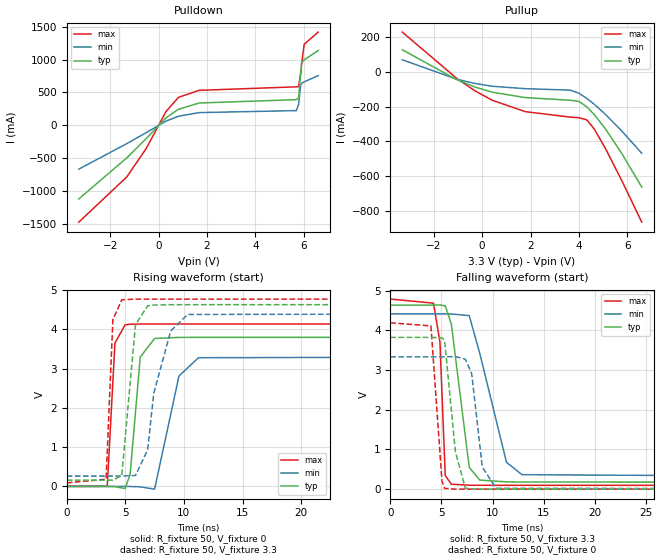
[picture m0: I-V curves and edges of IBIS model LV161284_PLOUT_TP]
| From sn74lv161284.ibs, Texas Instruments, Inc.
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[Model]   LV161284_PLOUT_TP
Model_type  Output
Vref =   0
Rref =   500
Cref =   50p
Vmeas =   1.4
| variable   typ   min   max
C_comp   9.71pF   6.01pF   13.91pF
| C_pullup   9.45pF   6.72pF   10.69pF
| C_pulldown   9.97pF   6.01pF   13.91pF
[Temperature Range]   40   100   -40
| Ambient temperature   25   85   -40
[Voltage range]   3.3   3   3.6
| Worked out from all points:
|   slope of the pulldown table from 0 to 0.495 V, typ, clamps not added: 2.94 ohm
|   slope of the pullup table from 0 to 0.495 V, typ, clamps not added: 26.2 ohm
|   rising waveform, R_fixture 50, V_fixture 0: 20-80 % time 587ps typ, 1.01ns min, 342ps max; typ from 0 V to 3.8 V
|   falling waveform, R_fixture 50, V_fixture 3.3: 20-80 % time 1.25ns typ, 2.38ns min, 422ps max; typ from 4.63 V to 0.171 V
|   rising waveform, R_fixture 50, V_fixture 3.3: 20-80 % time 694ps typ, 1.64ns min, 324ps max; typ from 0.161 V to 4.63 V
|   falling waveform, R_fixture 50, V_fixture 0: 20-80 % time 756ps typ, 826ps min, 627ps max; typ from 3.82 V to 0 V
[Pulldown]
| LV161284_PLOUT_TP
|   Voltage   I(typ)   I(min)   I(max)
-3.3V     -1.125A    -670.7mA   -1.479A
-1.315V   -498mA     -281.2mA   -789.1mA
-505mV    -202mA     -111.8mA   -352.1mA
305mV     111.9mA    62.04mA    207.4mA
820mV     243mA      136.8mA    424.4mA
1.675V    338.6mA    192.1mA    531.7mA
5.695V    389.6mA    222.6mA    585.2mA
5.79V     419.2mA    316.1mA    590.9mA
5.87V     779.2mA    606.5mA    773.1mA
5.915V    957.9mA    639.7mA    931mA
6.02V     996.7mA    661.1mA    1.234A
6.6V      1.139A     756.9mA    1.42A
[Pullup]
| LV161284_PLOUT_TP
|   Voltage   I(typ)   I(min)   I(max)
-3.3V     126mA      68.51mA    227.5mA
-1.06V    -45.03mA   -42.6mA    -37.28mA
-320mV    -86.79mA   -66.91mA   -108mA
420mV     -117.8mA   -83.56mA   -164.1mA
1.785V    -148.7mA   -97.45mA   -229.3mA
3.64V     -163.9mA   -105.8mA   -260.8mA
4.005V    -170.9mA   -123.9mA   -264.2mA
4.33V     -202.1mA   -153.5mA   -276.7mA
4.63V     -245.2mA   -186.3mA   -328.4mA
5.09V     -326.7mA   -244mA     -438.8mA
5.77V     -468.9mA   -340mA     -624.2mA
6.6V      -662.8mA   -468.2mA   -864.1mA
[Ramp]
| LV161284_PLOUT_TP
| variable   typ   min   max
dV/dt_r   2.32/5.98E-10   2.03/1.03E-09   2.49/3.52E-10
dV/dt_f   2.68/1.25E-09   2.48/2.38E-09   2.82/4.29E-10
R_load = 50
[Rising Waveform]
| LV161284_PLOUT_TP
R_fixture =   50
C_fixture =   0
L_fixture =   0
V_fixture =   0
V_fixture_min = 0
V_fixture_max = 0
|   Time   V(typ)   V(min)   V(max)
0s        17.54nV    82.91nV    413.1nV
3.455ns   118.9uV    -574.9nV   3.687mV
4.11ns    -5.713mV   -4.708uV   3.649V
4.975ns   -52.26mV   126.6uV    4.116V
5.405ns   303.8mV    -1.201mV   4.13V
6.27ns    3.295V     -10.72mV   4.136V
7.495ns   3.768V     -69.61mV   4.137V
9.575ns   3.796V     2.813V     4.137V
11.24ns   3.797V     3.278V     4.137V
70ns      3.797V     3.319V     4.137V
[Falling Waveform]
| LV161284_PLOUT_TP
R_fixture =   50
C_fixture =   0
L_fixture =   0
V_fixture =   3.3
V_fixture_min = 3
V_fixture_max = 3.6
|   Time   V(typ)   V(min)   V(max)
0s        4.635V     4.412V     4.787V
4.22ns    4.635V     4.412V     4.684V
4.85ns    4.638V     4.412V     3.707V
5.37ns    4.617V     4.412V     344.1mV
5.965ns   4.157V     4.411V     125.1mV
7.715ns   548.4mV    4.37V      99.04mV
8.75ns    228.4mV    3.416V     97.85mV
11.36ns   183.9mV    675.5mV    96.64mV
12.88ns   180.3mV    364mV      96.28mV
70ns      171.1mV    287.6mV    94.22mV
[Rising Waveform]
| LV161284_PLOUT_TP
R_fixture =   50
C_fixture =   0
L_fixture =   0
V_fixture =   3.3
V_fixture_min = 3
V_fixture_max = 3.6
|   Time   V(typ)   V(min)   V(max)
0s        161.3mV    265mV      91.9mV
3.355ns   161.3mV    265mV      183mV
3.935ns   160.9mV    265mV      4.248V
4.69ns    275.2mV    264.8mV    4.752V
5.865ns   4.121V     280.1mV    4.771V
6.9ns     4.6V       933.2mV    4.772V
7.425ns   4.62V      2.373V     4.772V
8.87ns    4.628V     3.96V      4.772V
10.31ns   4.629V     4.379V     4.772V
70ns      4.629V     4.415V     4.772V
[Falling Waveform]
| LV161284_PLOUT_TP
R_fixture =   50
C_fixture =   0
L_fixture =   0
V_fixture =   0
V_fixture_min = 0
V_fixture_max = 0
|   Time   V(typ)   V(min)   V(max)
0s        3.822V     3.331V     4.19V
3.97ns    3.822V     3.331V     4.111V
5.05ns    3.812V     3.331V     198.3mV
5.305ns   3.742V     3.331V     19.7mV
6.365ns   936.8mV    3.339V     2.096mV
7.335ns   24.9mV     3.273V     490.1uV
7.955ns   7.519mV    2.911V     309.7uV
8.99ns    1.947mV    558mV      190.7uV
10.33ns   559uV      23.45mV    125.3uV
70ns      6.295uV    10.89uV    7.719uV
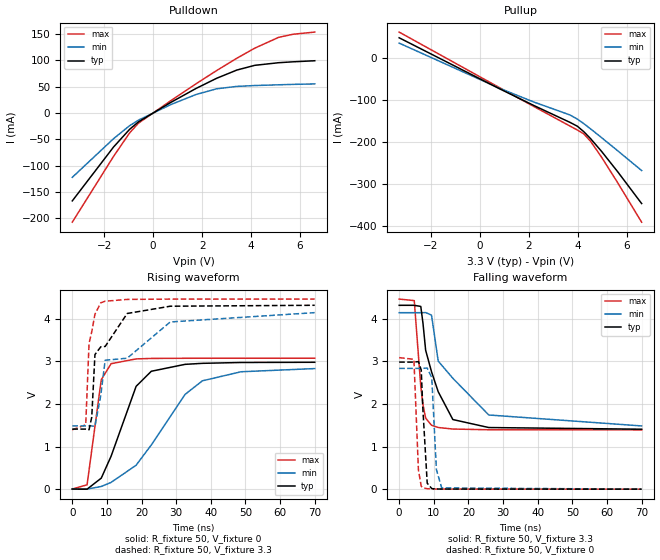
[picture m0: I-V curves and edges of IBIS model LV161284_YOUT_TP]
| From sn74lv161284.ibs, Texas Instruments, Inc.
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[Model]   LV161284_YOUT_TP
Model_type  Output
Vref =   3.3
Rref =   500
Cref =   50p
Vmeas =   1.4
| variable   typ   min   max
C_comp   3.71pF   2.21pF   4.90pF
| C_pullup   3.07pF   2.21pF   4.10pF
| C_pulldown   4.34pF   3.78pF   4.90pF
[Temperature Range]   40   100   -40
| Ambient temperature   25   85   -40
[Voltage range]   3.3   3   3.6
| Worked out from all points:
|   slope of the pulldown table from 0 to 0.495 V, typ, clamps not added: 36.1 ohm
|   slope of the pullup table from 0 to 0.495 V, typ, clamps not added: 34.3 ohm
|   rising waveform, R_fixture 50, V_fixture 0: 20-80 % time 7.91ns typ, 14.5ns min, 3ns max; typ from 0 V to 2.98 V
|   falling waveform, R_fixture 50, V_fixture 3.3: 20-80 % time 5.61ns typ, 11.6ns min, 1.86ns max; typ from 4.32 V to 1.41 V
|   rising waveform, R_fixture 50, V_fixture 3.3: 20-80 % time 6.84ns typ, 15.1ns min, 1.78ns max; typ from 1.41 V to 4.32 V
|   falling waveform, R_fixture 50, V_fixture 0: 20-80 % time 871ps typ, 949ps min, 733ps max; typ from 2.99 V to 0 V
[Pulldown]
| LV161284_YOUT_TP
|   Voltage   I(typ)   I(min)   I(max)
-3.3V     -167mA     -122.3mA   -207.4mA
-1.615V   -64.77mA   -48.94mA   -82.55mA
-960mV    -31.21mA   -24.31mA   -38.06mA
-595mV    -16.92mA   -13.7mA    -19.41mA
725mV     19.95mA    15.81mA    23.21mA
1.76V     46.53mA    34.97mA    55.41mA
2.595V    65.66mA    45.71mA    80.34mA
3.42V     81.28mA    50.25mA    103.7mA
4.15V     90.22mA    51.87mA    122.8mA
5.13V     95.22mA    53.28mA    143.4mA
5.715V    96.91mA    54.09mA    149.2mA
6.6V      98.93mA    54.94mA    153.3mA
[Pullup]
| LV161284_YOUT_TP
|   Voltage   I(typ)   I(min)   I(max)
-3.3V     47.15mA    34.51mA    60.63mA
760mV     -72.64mA   -71.61mA   -69.87mA
2.21V     -113.7mA   -105.4mA   -116.1mA
3.675V    -153.4mA   -135.8mA   -162.1mA
3.97V     -162.3mA   -145.4mA   -171.3mA
4.235V    -175.2mA   -156.3mA   -180.5mA
4.51V     -191.6mA   -168.5mA   -197.8mA
4.955V    -221.5mA   -189.1mA   -235.1mA
5.625V    -270.6mA   -220.8mA   -296.7mA
6.6V      -345.8mA   -267.6mA   -390mA
[Ramp]
| LV161284_YOUT_TP
| variable   typ   min   max
dV/dt_r   1.80/7.95E-09   1.71/1.46E-08   1.85/3.01E-09
dV/dt_f   1.75/5.61E-09   1.60/1.16E-08   1.85/1.86E-09
R_load = 50
[Rising Waveform]
| LV161284_YOUT_TP
R_fixture =   50
C_fixture =   0
L_fixture =   0
V_fixture =   0
V_fixture_min = 0
V_fixture_max = 0
|   Time   V(typ)   V(min)   V(max)
0s        403nV      1.053uV    7.613uV
4.275ns   -2.244mV   2.427uV    100.5mV
8.37ns    257mV      60.41mV    2.571V
11.21ns   772.7mV    157.1mV    2.946V
18.43ns   2.414V     560.1mV    3.058V
22.82ns   2.768V     1.037V     3.069V
32.55ns   2.93V      2.223V     3.073V
37.55ns   2.954V     2.543V     3.074V
48.71ns   2.974V     2.756V     3.074V
70ns      2.979V     2.831V     3.074V
[Falling Waveform]
| LV161284_YOUT_TP
R_fixture =   50
C_fixture =   0
L_fixture =   0
V_fixture =   3.3
V_fixture_min = 3
V_fixture_max = 3.6
|   Time   V(typ)   V(min)   V(max)
0s        4.32V      4.147V     4.467V
4.36ns    4.32V      4.147V     4.431V
6.245ns   4.294V     4.147V     2.416V
6.885ns   3.895V     4.147V     1.983V
7.645ns   3.266V     4.15V      1.672V
9.34ns    2.761V     4.09V      1.502V
11.28ns   2.289V     3.009V     1.449V
15.5ns    1.636V     2.606V     1.413V
25.87ns   1.448V     1.743V     1.396V
70ns      1.409V     1.486V     1.393V
[Rising Waveform]
| LV161284_YOUT_TP
R_fixture =   50
C_fixture =   0
L_fixture =   0
V_fixture =   3.3
V_fixture_min = 3
V_fixture_max = 3.6
|   Time   V(typ)   V(min)   V(max)
0s        1.409V     1.483V     1.393V
3.885ns   1.409V     1.483V     1.511V
4.84ns    1.393V     1.483V     3.417V
5.62ns    1.69V      1.483V     3.694V
6.545ns   3.16V      1.474V     4.109V
8.24ns    3.343V     2.207V     4.377V
9.495ns   3.35V      3.027V     4.413V
15.85ns   4.125V     3.074V     4.456V
28.28ns   4.296V     3.926V     4.463V
70ns      4.318V     4.145V     4.464V
[Falling Waveform]
| LV161284_YOUT_TP
R_fixture =   50
C_fixture =   0
L_fixture =   0
V_fixture =   0
V_fixture_min = 0
V_fixture_max = 0
|   Time   V(typ)   V(min)   V(max)
0s        2.986V     2.838V     3.091V
4.26ns    2.986V     2.838V     3.051V
5.565ns   2.997V     2.839V     448.9mV
6.375ns   2.801V     2.84V      69.09mV
6.81ns    1.94V      2.84V      35.58mV
8.1ns     140.8mV    2.847V     10.36mV
9.415ns   13.41mV    2.621V     4.764mV
10.75ns   4.422mV    461.5mV    3.198mV
12.28ns   2.353mV    30.04mV    2.299mV
70ns      55.74uV    69.46uV    179.5uV
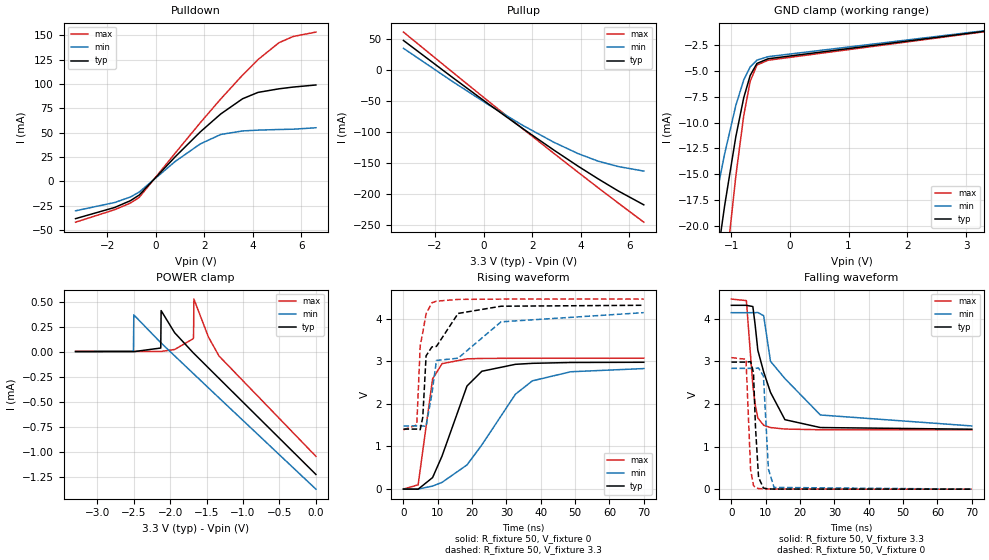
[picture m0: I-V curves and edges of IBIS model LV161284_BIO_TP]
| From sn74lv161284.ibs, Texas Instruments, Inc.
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[Model]   LV161284_BIO_TP
Model_type  I/O
Vinl=0.8
Vinh=2.0
Enable   Active-High
Vref =   3.3
Rref =   500
Cref =   50p
Vmeas =   1.4
| variable   typ   min   max
C_comp   5.52pF   4.67pF   6.22pF
| C_pullup   3.90pF   2.99pF   4.78pF
| C_pulldown   5.17pF   4.57pF   5.68pF
| C_tri-state   5.52pF   4.67pF   6.22pF
[Temperature Range]   40   100   -40
| Ambient temperature   25   85   -40
[Voltage range]   3.3   3   3.6
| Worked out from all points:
|   slope of the pulldown table from 0 to 0.495 V, typ, clamps not added: 37 ohm
|   slope of the pullup table from 0 to 0.495 V, typ, clamps not added: 35.2 ohm
|   rising waveform, R_fixture 50, V_fixture 0: 20-80 % time 7.93ns typ, 14.5ns min, 3.04ns max; typ from 0 V to 2.98 V
|   falling waveform, R_fixture 50, V_fixture 3.3: 20-80 % time 5.65ns typ, 11.6ns min, 1.89ns max; typ from 4.32 V to 1.41 V
|   rising waveform, R_fixture 50, V_fixture 3.3: 20-80 % time 6.87ns typ, 15.1ns min, 1.8ns max; typ from 1.41 V to 4.32 V
|   falling waveform, R_fixture 50, V_fixture 0: 20-80 % time 917ps typ, 992ps min, 764ps max; typ from 2.99 V to 0 V
[GND Clamp]
| LV161284_BIO_TP
|   Voltage   I(typ)   I(min)   I(max)
-3.3V     -132.9mA   -95.54mA   -170.5mA
-1.54V    -36.32mA   -26.12mA   -50.92mA
-1.495V   -34.24mA   -24.64mA   -48.09mA
-1.295V   -25.43mA   -18.32mA   -35.84mA
-1.275V   -24.59mA   -17.72mA   -34.65mA
-1.11V    -18mA      -13.01mA   -25.13mA
-920mV    -11.37mA   -8.353mA   -15.17mA
-785mV    -7.61mA    -5.896mA   -9.329mA
-675mV    -5.466mA   -4.642mA   -6.029mA
-560mV    -4.309mA   -3.992mA   -4.463mA
-370mV    -3.864mA   -3.66mA    -4.005mA
3.3V      -1.226mA   -1.168mA   -1.268mA
[POWER Clamp]
| LV161284_BIO_TP
|   Voltage   I(typ)   I(min)   I(max)
-3.3V     318.9nA    13.56nA    4.426uA
-2.505V   202.9nA    4.995uA    2.684uA
-2.5V     202.5nA    367uA      2.674uA
-2.13V    36.28uA    89.82uA    2.09uA
-2.125V   410uA      86.37uA    2.092uA
-1.94V    189.5uA    -41.39uA   21.68uA
-1.685V   -10.57uA   -217.2uA   128.8uA
-1.68V    -14.2uA    -220.7uA   137.3uA
-1.675V   -17.83uA   -224.1uA   525.1uA
-1.475V   -162.4uA   -361.8uA   145uA
-1.33V    -267.1uA   -461.6uA   -43.55uA
-48.03fV  -1.226mA   -1.373mA   -1.045mA
[Pulldown]
| LV161284_BIO_TP
|   Voltage   I(typ)   I(min)   I(max)
-3.3V     -38.49mA   -30.42mA   -42.13mA
-1.69V    -27.01mA   -21.92mA   -29.3mA
-1.045V   -20.07mA   -16.3mA    -22.51mA
-680mV    -14.27mA   -11.21mA   -16.75mA
810mV     25.23mA    20.41mA    29.02mA
1.84V     50.74mA    38.38mA    60.19mA
2.68V     69.12mA    48.05mA    84.54mA
3.58V     84.76mA    51.67mA    109.1mA
4.215V    91.3mA     52.52mA    125mA
5.08V     94.99mA    53.16mA    142.4mA
5.665V    96.78mA    53.47mA    148.8mA
6.6V      98.93mA    54.94mA    153.3mA
[Pullup]
| LV161284_BIO_TP
|   Voltage   I(typ)   I(min)   I(max)
-3.3V     47.15mA    34.51mA    60.62mA
-1.27V    -12.61mA   -19.15mA   -4.139mA
190mV     -54.74mA   -55.98mA   -50.36mA
1.59V     -93.97mA   -88.92mA   -94.17mA
2.895V    -129.2mA   -116.6mA   -134.5mA
3.9V      -155.3mA   -135mA     -165.1mA
4.715V    -175.4mA   -147mA     -189.7mA
5.54V     -194.8mA   -155.6mA   -214.2mA
6.6V      -217.3mA   -163mA     -245.2mA
[Ramp]
| LV161284_BIO_TP
| variable   typ   min   max
dV/dt_r   1.80/7.97E-09   1.71/1.46E-08   1.85/3.05E-09
dV/dt_f   1.75/5.64E-09   1.60/1.16E-08   1.85/1.89E-09
R_load = 50
[Rising Waveform]
| LV161284_BIO_TP
R_fixture =   50
C_fixture =   0
L_fixture =   0
V_fixture =   0
V_fixture_min = 0
V_fixture_max = 0
|   Time   V(typ)   V(min)   V(max)
0s        419.4nV    1.058uV    7.728uV
4.275ns   -2.507mV   2.249uV    99.21mV
8.485ns   270.1mV    69.85mV    2.588V
11.23ns   774.9mV    156.9mV    2.946V
18.5ns    2.421V     566.3mV    3.059V
22.83ns   2.768V     1.038V     3.069V
32.62ns   2.931V     2.229V     3.073V
37.56ns   2.954V     2.543V     3.074V
48.72ns   2.974V     2.756V     3.074V
70ns      2.979V     2.831V     3.074V
[Falling Waveform]
| LV161284_BIO_TP
R_fixture =   50
C_fixture =   0
L_fixture =   0
V_fixture =   3.3
V_fixture_min = 3
V_fixture_max = 3.6
|   Time   V(typ)   V(min)   V(max)
0s        4.32V      4.147V     4.467V
4.365ns   4.32V      4.147V     4.431V
6.255ns   4.292V     4.147V     2.438V
6.915ns   3.864V     4.147V     1.994V
7.705ns   3.265V     4.151V     1.672V
9.4ns     2.756V     4.076V     1.501V
11.39ns   2.275V     3.006V     1.448V
15.59ns   1.633V     2.599V     1.413V
25.92ns   1.448V     1.743V     1.396V
70ns      1.409V     1.486V     1.393V
[Rising Waveform]
| LV161284_BIO_TP
R_fixture =   50
C_fixture =   0
L_fixture =   0
V_fixture =   3.3
V_fixture_min = 3
V_fixture_max = 3.6
|   Time   V(typ)   V(min)   V(max)
0s        1.409V     1.483V     1.393V
3.885ns   1.409V     1.483V     1.507V
4.875ns   1.395V     1.483V     3.364V
5.625ns   1.686V     1.483V     3.678V
6.59ns    3.131V     1.473V     4.119V
8.295ns   3.34V      2.246V     4.377V
9.61ns    3.352V     3.022V     4.415V
15.91ns   4.126V     3.075V     4.456V
28.42ns   4.296V     3.929V     4.463V
70ns      4.318V     4.145V     4.464V
[Falling Waveform]
| LV161284_BIO_TP
R_fixture =   50
C_fixture =   0
L_fixture =   0
V_fixture =   0
V_fixture_min = 0
V_fixture_max = 0
|   Time   V(typ)   V(min)   V(max)
0s        2.986V     2.838V     3.091V
4.26ns    2.986V     2.838V     3.052V
5.605ns   2.997V     2.839V     453.7mV
6.445ns   2.73V      2.84V      85.95mV
7.015ns   1.469V     2.84V      36.49mV
7.915ns   275.2mV    2.846V     14.17mV
9.34ns    25.62mV    2.659V     5.229mV
10.78ns   5.756mV    474.3mV    3.268mV
12.42ns   2.467mV    40.81mV    2.279mV
70ns      57.1uV     71.29uV    180.6uV
